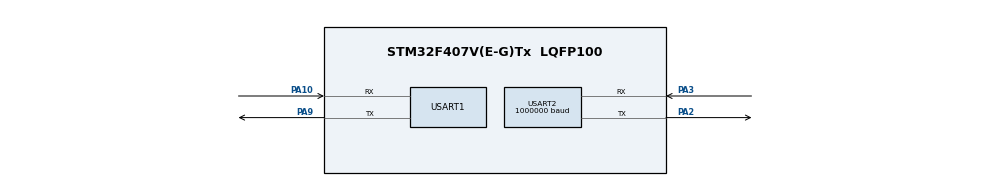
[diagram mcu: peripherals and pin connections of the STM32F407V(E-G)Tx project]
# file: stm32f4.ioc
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Mcu.Family=STM32F4
Mcu.Name=STM32F407V(E-G)Tx
Mcu.Package=LQFP100
NVIC.PriorityGroup=NVIC_PRIORITYGROUP_4
PA10.Mode=Asynchronous
PA10.Signal=USART1_RX
PA13.Mode=JTAG_5_pins
PA13.Signal=SYS_JTMS-SWDIO
PA14.Mode=JTAG_5_pins
PA14.Signal=SYS_JTCK-SWCLK
PA15.Mode=JTAG_5_pins
PA15.Signal=SYS_JTDI
PA2.Mode=Asynchronous
PA2.Signal=USART2_TX
PA3.Mode=Asynchronous
PA3.Signal=USART2_RX
PA9.Mode=Asynchronous
PA9.Signal=USART1_TX
PB3.Mode=JTAG_5_pins
PB3.Signal=SYS_JTDO-SWO
PB4.Mode=JTAG_5_pins
PB4.Signal=SYS_JTRST
PH0-OSC_IN.Mode=HSE-External-Oscillator
PH0-OSC_IN.Signal=RCC_OSC_IN
PH1-OSC_OUT.Mode=HSE-External-Oscillator
PH1-OSC_OUT.Signal=RCC_OSC_OUT
ProjectManager.HeapSize=0x200
ProjectManager.StackSize=0x400
ProjectManager.TargetToolchain=MDK-ARM V5.27
RCC.48MHZClocksFreq_Value=84000000
RCC.AHBFreq_Value=168000000
RCC.APB1CLKDivider=RCC_HCLK_DIV4
RCC.APB1Freq_Value=42000000
RCC.APB1TimFreq_Value=84000000
RCC.APB2CLKDivider=RCC_HCLK_DIV2
RCC.APB2Freq_Value=84000000
RCC.APB2TimFreq_Value=168000000
RCC.CortexFreq_Value=168000000
RCC.HCLKFreq_Value=168000000
RCC.HSE_VALUE=8000000
RCC.HSI_VALUE=16000000
RCC.LSE_VALUE=32768
RCC.PLLM=4
RCC.PLLN=168
RCC.PLLSourceVirtual=RCC_PLLSOURCE_HSE
RCC.SYSCLKFreq_VALUE=168000000
RCC.SYSCLKSource=RCC_SYSCLKSOURCE_PLLCLK
RCC.VCOOutputFreq_Value=336000000
USART1.VirtualMode=VM_ASYNC
USART2.BaudRate=1000000
USART2.VirtualMode=VM_ASYNC
board=custom

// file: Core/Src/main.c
/* USER CODE BEGIN Header */
/**
  ******************************************************************************
  * @file           : main.c
  * @brief          : Main program body
  ******************************************************************************
  * @attention
  *
  * <h2><center>&copy; Copyright (c) 2024 STMicroelectronics.
  * All rights reserved.</center></h2>
  *
  * This software component is licensed by ST under BSD 3-Clause license,
  * the "License"; You may not use this file except in compliance with the
  * License. You may obtain a copy of the License at:
  *                        opensource.org/licenses/BSD-3-Clause
  *
  ******************************************************************************
  */
/* USER CODE END Header */
#include "main.h"

/* USER CODE BEGIN Includes */
#include <stdio.h>
#include <../../SCSLib/SCServo.h>
/* USER CODE END Includes */

/* USER CODE BEGIN PD */
//FT舵机总线切换延时(单位:us)，要求大�?10us，按实际硬件收发切换时间调整
#define FT_BUS_DELAY_US 20
/* USER CODE END PD */

UART_HandleTypeDef huart1;
UART_HandleTypeDef huart2;

void SystemClock_Config(void);
static void MX_GPIO_Init(void);
static void MX_USART1_UART_Init(void);
static void MX_USART2_UART_Init(void);
/* USER CODE BEGIN PFP */
void ftBus_DelayInit(void);
void examples(void);
void setup(void);
/* USER CODE END PFP */

/* USER CODE BEGIN 0 */
//printf函数串口重定�?
int fputc(int c, FILE *f)
{
	HAL_UART_Transmit(&huart1, (uint8_t *)&c, 1, 100);
	return c;
}

//FT舵机串口指令发�?�函�?
void ftUart_Send(uint8_t *nDat , int nLen)
{
	//发�?�前丢弃接收残留，避免上�?帧超时残字节干扰后面的帧头检�?
	__HAL_UART_CLEAR_OREFLAG(&huart2);
	while(__HAL_UART_GET_FLAG(&huart2, UART_FLAG_RXNE) != RESET){
		(void)huart2.Instance->DR;
	}
	HAL_UART_Transmit(&huart2, nDat, nLen, 100);
}

//FT舵机串口指令应答接收函数
int ftUart_Read(uint8_t *nDat, int nLen)
{
	if(HAL_OK!=HAL_UART_Receive(&huart2, nDat, nLen, 100)){
		return 0;
	}else{
		return nLen;
	}
}

//FT舵机总线切换延时(DWT周期计数�?)初始化，仅需调用�?�?
void ftBus_DelayInit(void)
{
	CoreDebug->DEMCR |= CoreDebug_DEMCR_TRCENA_Msk;
	DWT->CTRL |= DWT_CTRL_CYCCNTENA_Msk;
}

//FT舵机总线切换延时，时间大�?10us(FT_BUS_DELAY_US)
//基于DWT周期计数器，精度1个内核周期，支持任意长度延时
//注意：DWT仅Cortex-M3/M4/M7保证存在；M0/M0+/M1没有DWT，M23/M33等为可�?�实�?
void ftBus_Delay(void)
{
	if((DWT->CTRL & DWT_CTRL_CYCCNTENA_Msk) == 0){
		ftBus_DelayInit();//兜底：未初始化时自动使能，避免死循环
	}
	uint32_t start = DWT->CYCCNT;
	uint32_t ticks = (SystemCoreClock/1000000U)*FT_BUS_DELAY_US;//延时对应的内核周期数
	while((DWT->CYCCNT - start) < ticks){
	}
}

/* USER CODE END 0 */

int main(void)
{

  /* MCU Configuration--------------------------------------------------------*/

  /* Reset of all peripherals, Initializes the Flash interface and the Systick. */
  HAL_Init();

  /* Configure the system clock */
  SystemClock_Config();

  /* Initialize all configured peripherals */
  MX_GPIO_Init();
  MX_USART1_UART_Init();
  MX_USART2_UART_Init();
  /* USER CODE BEGIN 2 */
	//等待舵机上电启动
	HAL_Delay(1000);
	//总线切换延时(DWT周期计数�?)初始�?
	ftBus_DelayInit();
	//舵机库初始化配置
	setup();
  /* USER CODE END 2 */

  /* Infinite loop */
  /* USER CODE BEGIN WHILE */
  while (1)
  {
		examples();
    /* USER CODE END WHILE */

  }
}

void SystemClock_Config(void)
{
  RCC_OscInitTypeDef RCC_OscInitStruct = {0};
  RCC_ClkInitTypeDef RCC_ClkInitStruct = {0};

  /** Initializes the RCC Oscillators according to the specified parameters
  * in the RCC_OscInitTypeDef structure.
  */
  RCC_OscInitStruct.OscillatorType = RCC_OSCILLATORTYPE_HSE;
  RCC_OscInitStruct.HSEState = RCC_HSE_ON;
  RCC_OscInitStruct.HSEPredivValue = RCC_HSE_PREDIV_DIV1;
  RCC_OscInitStruct.HSIState = RCC_HSI_ON;
  RCC_OscInitStruct.PLL.PLLState = RCC_PLL_ON;
  RCC_OscInitStruct.PLL.PLLSource = RCC_PLLSOURCE_HSE;
  RCC_OscInitStruct.PLL.PLLMUL = RCC_PLL_MUL9;
  if (HAL_RCC_OscConfig(&RCC_OscInitStruct) != HAL_OK)
  {
    Error_Handler();
  }
  /** Initializes the CPU, AHB and APB buses clocks
  */
  RCC_ClkInitStruct.ClockType = RCC_CLOCKTYPE_HCLK|RCC_CLOCKTYPE_SYSCLK
                              |RCC_CLOCKTYPE_PCLK1|RCC_CLOCKTYPE_PCLK2;
  RCC_ClkInitStruct.SYSCLKSource = RCC_SYSCLKSOURCE_PLLCLK;
  RCC_ClkInitStruct.AHBCLKDivider = RCC_SYSCLK_DIV1;
  RCC_ClkInitStruct.APB1CLKDivider = RCC_HCLK_DIV2;
  RCC_ClkInitStruct.APB2CLKDivider = RCC_HCLK_DIV1;

  if (HAL_RCC_ClockConfig(&RCC_ClkInitStruct, FLASH_LATENCY_2) != HAL_OK)
  {
    Error_Handler();
  }
}

static void MX_USART1_UART_Init(void)
{

  huart1.Instance = USART1;
  huart1.Init.BaudRate = 115200;
  huart1.Init.WordLength = UART_WORDLENGTH_8B;
  huart1.Init.StopBits = UART_STOPBITS_1;
  huart1.Init.Parity = UART_PARITY_NONE;
  huart1.Init.Mode = UART_MODE_TX_RX;
  huart1.Init.HwFlowCtl = UART_HWCONTROL_NONE;
  huart1.Init.OverSampling = UART_OVERSAMPLING_16;
  if (HAL_UART_Init(&huart1) != HAL_OK)
  {
    Error_Handler();
  }

}

static void MX_USART2_UART_Init(void)
{

  huart2.Instance = USART2;
  huart2.Init.BaudRate = 1000000;
  huart2.Init.WordLength = UART_WORDLENGTH_8B;
  huart2.Init.StopBits = UART_STOPBITS_1;
  huart2.Init.Parity = UART_PARITY_NONE;
  huart2.Init.Mode = UART_MODE_TX_RX;
  huart2.Init.HwFlowCtl = UART_HWCONTROL_NONE;
  huart2.Init.OverSampling = UART_OVERSAMPLING_16;
  if (HAL_UART_Init(&huart2) != HAL_OK)
  {
    Error_Handler();
  }

}

static void MX_GPIO_Init(void)
{

  /* GPIO Ports Clock Enable */
  __HAL_RCC_GPIOA_CLK_ENABLE();
  __HAL_RCC_GPIOB_CLK_ENABLE();

}

void Error_Handler(void)
{
  __disable_irq();
  while (1)
  {
  }
}

/************************ (C) COPYRIGHT STMicroelectronics *****END OF FILE****/
